VERSION 5.7 ;
  NOWIREEXTENSIONATPIN ON ;
  DIVIDERCHAR "/" ;
  BUSBITCHARS "[]" ;
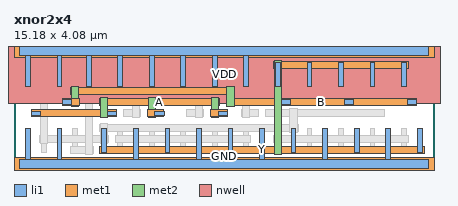
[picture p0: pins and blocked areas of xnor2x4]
MACRO xnor2x4
  CLASS BLOCK ;
  FOREIGN xnor2x4 ;
  ORIGIN 0.000 0.000 ;
  SIZE 15.180 BY 4.080 ;
  PIN A
    ANTENNAGATEAREA 2.612400 ;
    PORT
      LAYER li1 ;
        RECT 0.635 1.745 0.965 1.915 ;
        RECT 3.385 1.745 3.715 1.915 ;
        RECT 5.095 1.745 5.425 1.915 ;
        RECT 7.375 1.745 7.705 1.915 ;
      LAYER met1 ;
        RECT 3.105 2.100 7.415 2.360 ;
        RECT 0.640 1.700 3.710 1.960 ;
        RECT 4.815 1.700 5.420 1.960 ;
        RECT 7.095 1.700 7.700 1.960 ;
      LAYER met2 ;
        RECT 3.135 1.670 3.395 2.390 ;
        RECT 4.845 1.670 5.105 2.390 ;
        RECT 7.125 1.670 7.385 2.390 ;
    END
  END A
  PIN B
    ANTENNAGATEAREA 2.612400 ;
    PORT
      LAYER li1 ;
        RECT 1.765 2.145 2.095 2.315 ;
        RECT 9.655 2.145 9.985 2.315 ;
        RECT 11.935 2.145 12.265 2.315 ;
        RECT 14.215 2.145 14.545 2.315 ;
      LAYER met1 ;
        RECT 2.055 2.500 7.985 2.760 ;
        RECT 1.770 2.100 2.375 2.360 ;
        RECT 7.665 2.100 14.540 2.360 ;
      LAYER met2 ;
        RECT 2.085 2.070 2.345 2.790 ;
        RECT 7.695 2.070 7.955 2.790 ;
    END
  END B
  PIN Y
    ANTENNADIFFAREA 3.015600 ;
    PORT
      LAYER li1 ;
        RECT 9.450 2.800 9.620 3.680 ;
        RECT 10.590 2.800 10.760 3.680 ;
        RECT 11.730 2.800 11.900 3.680 ;
        RECT 12.870 2.800 13.040 3.680 ;
        RECT 14.010 2.800 14.180 3.680 ;
        RECT 3.180 0.400 3.350 1.280 ;
        RECT 5.460 0.400 5.630 1.280 ;
        RECT 7.740 0.400 7.910 1.280 ;
        RECT 10.020 0.400 10.190 1.280 ;
        RECT 12.300 0.400 12.470 1.280 ;
        RECT 14.580 0.400 14.750 1.280 ;
      LAYER met1 ;
        RECT 9.375 3.440 14.255 3.700 ;
        RECT 3.105 0.380 14.825 0.640 ;
      LAYER met2 ;
        RECT 9.405 0.350 9.665 3.730 ;
    END
  END Y
  PIN VDD
    ANTENNADIFFAREA 6.704400 ;
    PORT
      LAYER nwell ;
        RECT -0.230 2.200 15.410 4.410 ;
      LAYER li1 ;
        RECT 0.210 3.915 14.970 4.245 ;
        RECT 0.430 2.800 0.600 3.915 ;
        RECT 1.560 2.800 1.730 3.915 ;
        RECT 2.620 2.800 2.790 3.915 ;
        RECT 3.750 2.800 3.920 3.915 ;
        RECT 4.890 2.800 5.060 3.915 ;
        RECT 6.030 2.800 6.200 3.915 ;
        RECT 7.170 2.800 7.340 3.915 ;
        RECT 8.310 2.800 8.480 3.915 ;
      LAYER met1 ;
        RECT 0.000 3.840 15.180 4.320 ;
    END
  END VDD
  PIN GND
    ANTENNADIFFAREA 5.952600 ;
    PORT
      LAYER li1 ;
        RECT 0.430 0.165 0.600 1.280 ;
        RECT 1.560 0.165 1.730 1.280 ;
        RECT 4.320 0.165 4.490 1.280 ;
        RECT 6.600 0.165 6.770 1.280 ;
        RECT 8.880 0.165 9.050 1.280 ;
        RECT 11.160 0.165 11.330 1.280 ;
        RECT 13.440 0.165 13.610 1.280 ;
        RECT 0.210 -0.165 14.970 0.165 ;
      LAYER met1 ;
        RECT 0.000 -0.240 15.180 0.240 ;
    END
  END GND
  OBS
      LAYER li1 ;
        RECT 1.000 2.800 1.170 3.680 ;
        RECT 2.130 2.800 2.300 3.680 ;
        RECT 3.180 2.800 3.350 3.680 ;
        RECT 4.320 2.800 4.490 3.680 ;
        RECT 5.460 2.800 5.630 3.680 ;
        RECT 6.600 2.800 6.770 3.680 ;
        RECT 7.740 2.800 7.910 3.680 ;
        RECT 8.880 2.800 9.050 3.680 ;
        RECT 10.020 2.800 10.190 3.680 ;
        RECT 11.160 2.800 11.330 3.680 ;
        RECT 12.300 2.800 12.470 3.680 ;
        RECT 13.440 2.800 13.610 3.680 ;
        RECT 14.580 2.800 14.750 3.680 ;
        RECT 3.955 1.745 4.285 1.915 ;
        RECT 6.235 1.745 6.565 1.915 ;
        RECT 8.515 1.745 8.845 1.915 ;
        RECT 9.085 1.745 9.415 1.915 ;
        RECT 10.795 1.745 11.125 1.915 ;
        RECT 13.075 1.745 13.405 1.915 ;
        RECT 1.000 0.400 1.170 1.280 ;
        RECT 2.130 0.400 2.300 1.280 ;
        RECT 3.750 0.400 3.920 1.280 ;
        RECT 4.890 0.400 5.060 1.280 ;
        RECT 6.030 0.400 6.200 1.280 ;
        RECT 7.170 0.400 7.340 1.280 ;
        RECT 8.310 0.400 8.480 1.280 ;
        RECT 9.450 0.400 9.620 1.280 ;
        RECT 10.590 0.400 10.760 1.280 ;
        RECT 11.730 0.400 11.900 1.280 ;
        RECT 12.870 0.400 13.040 1.280 ;
        RECT 14.010 0.400 14.180 1.280 ;
      LAYER met1 ;
        RECT 2.055 3.440 8.555 3.700 ;
        RECT 0.925 3.040 1.245 3.300 ;
        RECT 3.105 3.040 14.825 3.300 ;
        RECT 3.960 1.700 4.565 1.960 ;
        RECT 6.240 1.700 6.845 1.960 ;
        RECT 8.235 1.700 8.840 1.960 ;
        RECT 9.090 1.700 13.400 1.960 ;
        RECT 3.105 1.180 10.265 1.440 ;
        RECT 0.925 0.780 3.425 1.040 ;
        RECT 3.675 0.780 8.555 1.040 ;
        RECT 9.375 0.780 14.255 1.040 ;
        RECT 2.055 0.380 2.865 0.640 ;
      LAYER met2 ;
        RECT 0.955 0.750 1.215 3.330 ;
        RECT 2.575 0.350 2.835 3.730 ;
        RECT 4.275 1.670 4.535 3.730 ;
        RECT 6.555 1.670 6.815 3.730 ;
        RECT 8.265 1.670 8.525 3.730 ;
        RECT 3.135 0.750 3.395 1.470 ;
        RECT 9.975 1.150 10.235 1.990 ;
  END
END xnor2x4
END LIBRARY

